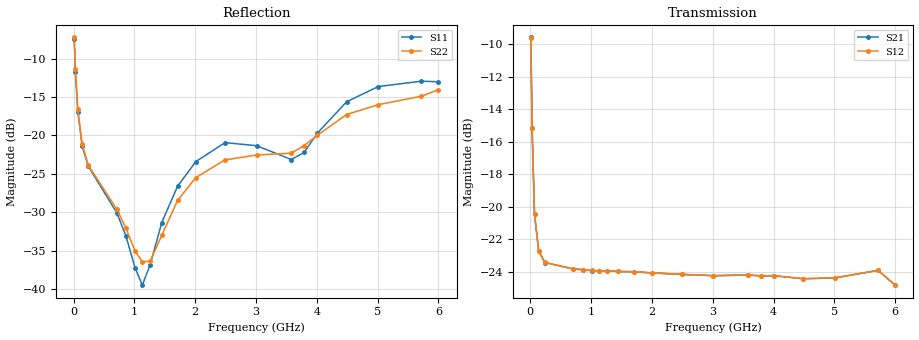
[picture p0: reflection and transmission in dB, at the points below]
! Integrated Device Technology
! Corporate Headquarters
! 6024 Silver Creek Valley Road
! San Jose, CA 95138  USA
! Phone:  1-408-284-8200
! Toll Free:  1-800-223-1366
! Webpage:  http://www.idt.com/
! Timing and RF Division
! 515 Groton Road, Suite 102
! Westford, MA 01886-6024
! Device:  F1951
! Description: 6-bit 0.5 dB Digital Step Attenuator
! Frequency:  100.0 -  4000.00 MHz
! Package:  4x4 mm Thin QFN Plastic Package: 24 pin
! Ports:  2 RF, 6 DC
!  Pin  1  = NC
!  Pin  2  = RF1  =  Port 1
!  Pin  3  = GND
!  Pin  4  = NC
!  Pin  5  = Serial Data Out (SDO)
!  Pin  6  = NC
!  Pin  7  = Reset Bar ( RSTb)
!  Pin  8  = Clock (CLK)
!  Pin  9  = Chip Select Bar (CSb)
!  Pin 10  = NC
!  Pin 11  = Serial Data In (SDI)
!  Pin 12  = NC
!  Pin 13  = NC
!  Pin 14  = VDD
!  Pin 15  = NC
!  Pin 16  = GND
!  Pin 17  = RF2  =  Port 2
!  Pin 18  = NC
!  Pin 19  = GND
!  Pin 20  = GND
!  Pin 21  = GND
!  Pin 22  = GND
!  Pin 23  = GND
!  Pin 24  = GND
! State:  46
! Atten State:  23.0 dB
! Voltage:  +3.30 Volts
! Current:  0.480 mA
! Data:  The device was measured on a F195X evaluation board which has
!  individual transmission lines to the RF pins.  Data was collected
!  de-embedded using a Automatic Fixture Removal [AFR] (Keysight Technologies).
!  The reference plane is the edge of the package pin.
! Misc:  Lot Code  1225BCA
!  Action Tracker AT0399
! Date Measured:  2018-09-13
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# GHz S dB R 50
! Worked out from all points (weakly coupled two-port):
!   600 points, 10 MHz to 6 GHz, reference 50 ohm
!   highest |S21| = -9.59 dB at 10 MHz (marker M1); lowest = -24.8 dB at 6 GHz (marker M2)
!   lowest |S11| = -39.5 dB at 1.13 GHz (marker M3), VSWR 1.02, Z = 49 + j0.175 ohm
!   |S11| at or under -10 dB: 21.2 MHz to end of sweep
!   |S22| runs from -36.9 to -7.2 dB; largest |S21 - S12| = 0.00019
!   S11 on the Smith chart (normalised r, x): 10 MHz: 1.74, -1.00; 30 MHz: 1.13, -0.55; 70 MHz: 0.97, -0.28; 1.45 GHz: 0.98, +0.05; 6 GHz: 0.81, +0.37
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0.01  -7.38 -33.3  -9.59 -32.3  -9.60 -32.2  -7.23 -31.8
0.03  -11.75 -62.1  -15.18 -49.1  -15.18 -49.2  -11.36 -60.9
0.07  -16.95 -86.9  -20.47 -41.0  -20.47 -41.0  -16.59 -86.5
0.14  -21.34 -108.1  -22.74 -26.7  -22.74 -26.7  -21.07 -107.2
0.24  -23.99 -122.4  -23.43 -18.7  -23.42 -18.7  -23.87 -121.9
0.71  -30.06 -134.3  -23.83 -15.4  -23.83 -15.5  -29.60 -137.5
0.86  -33.06 -138.6  -23.87 -16.7  -23.87 -16.7  -32.06 -142.0
1.01  -37.21 -154.4  -23.93 -18.0  -23.92 -18.0  -35.04 -151.9
1.13  -39.48 170.3  -23.94 -19.0  -23.94 -19.0  -36.44 -170.0
1.26  -36.81 131.7  -23.94 -20.5  -23.95 -20.4  -36.33 164.0
1.45  -31.33 116.3  -23.98 -22.7  -23.98 -22.7  -33.00 141.4
1.71  -26.61 115.6  -24.00 -25.9  -24.00 -25.8  -28.46 131.7
2.01  -23.40 123.0  -24.07 -29.7  -24.07 -29.7  -25.48 134.1
2.49  -20.93 136.1  -24.16 -35.7  -24.16 -35.7  -23.18 141.5
3.01  -21.33 146.0  -24.24 -42.0  -24.24 -41.9  -22.54 145.0
3.58  -23.13 124.3  -24.20 -48.8  -24.20 -48.9  -22.31 127.7
3.79  -22.21 108.6  -24.25 -51.4  -24.25 -51.4  -21.32 120.8
4.01  -19.69 100.2  -24.24 -54.1  -24.24 -54.1  -19.96 115.4
4.49  -15.61 98.6  -24.43 -59.6  -24.42 -59.6  -17.27 113.8
5.01  -13.63 107.4  -24.38 -63.8  -24.37 -63.7  -15.99 116.4
5.72  -12.93 112.4  -23.91 -75.5  -23.91 -75.5  -14.89 109.4
6  -13.01 106.1  -24.82 -79.0  -24.82 -79.0  -14.03 105.7
